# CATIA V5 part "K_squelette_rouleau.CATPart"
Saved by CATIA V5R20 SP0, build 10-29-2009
Part number: squelette_rouleau
Publications: "Point_centre_liaison_pivot_rouleau", "Droite.2", "droite_rouleau", "axe_pivot3rouleau"
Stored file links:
  G:\Khaled_CFAO_2011\SIL\SIL_GR2\pfradet\pfradet\Khaled\CAD_ThinkMOTION\K_squelette_rouleau.CATPart
  G:\Khaled_CFAO_2011\SIL\SIL_GR2\pfradet\pfradet\squelette.CATProduct

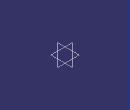
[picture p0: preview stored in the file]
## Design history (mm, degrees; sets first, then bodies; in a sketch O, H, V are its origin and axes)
Body1 (main body)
